VERSION 5.8 ;
BUSBITCHARS "[]" ;
DIVIDERCHAR "/" ;
UNITS
    DATABASE MICRONS 1000 ;
END UNITS

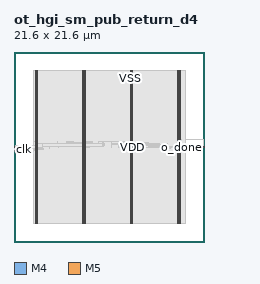
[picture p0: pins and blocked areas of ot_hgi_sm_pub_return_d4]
MACRO ot_hgi_sm_pub_return_d4
  FOREIGN ot_hgi_sm_pub_return_d4 0 0 ;
  CLASS BLOCK ;
  SIZE 21.6 BY 21.6 ;
  PIN clk
    DIRECTION INPUT ;
    USE SIGNAL ;
    PORT
      LAYER M4 ;
        RECT  0 10.512 0.084 10.536 ;
    END
  END clk
  PIN i_done
    DIRECTION INPUT ;
    USE SIGNAL ;
    PORT
      LAYER M4 ;
        RECT  0 10.608 0.084 10.632 ;
    END
  END i_done
  PIN i_fault
    DIRECTION INPUT ;
    USE SIGNAL ;
    PORT
      LAYER M4 ;
        RECT  0 10.704 0.084 10.728 ;
    END
  END i_fault
  PIN o_done
    DIRECTION OUTPUT ;
    USE SIGNAL ;
    PORT
      LAYER M4 ;
        RECT  21.516 10.704 21.6 10.728 ;
    END
  END o_done
  PIN o_fault
    DIRECTION OUTPUT ;
    USE SIGNAL ;
    PORT
      LAYER M4 ;
        RECT  21.516 10.8 21.6 10.824 ;
    END
  END o_fault
  PIN rn
    DIRECTION INPUT ;
    USE SIGNAL ;
    PORT
      LAYER M4 ;
        RECT  0 10.8 0.084 10.824 ;
    END
  END rn
  PIN VDD
    DIRECTION INOUT ;
    USE POWER ;
    PORT
      LAYER M5 ;
        RECT  18.792 2.151 18.912 19.449 ;
        RECT  13.392 2.151 13.512 19.449 ;
        RECT  7.992 2.151 8.112 19.449 ;
        RECT  2.592 2.151 2.712 19.449 ;
    END
  END VDD
  PIN VSS
    DIRECTION INOUT ;
    USE GROUND ;
    PORT
      LAYER M5 ;
        RECT  18.6 2.137 18.72 19.463 ;
        RECT  13.2 2.137 13.32 19.463 ;
        RECT  7.8 2.137 7.92 19.463 ;
        RECT  2.4 2.137 2.52 19.463 ;
    END
  END VSS
  # OT_OBS_CLOSED layer=M5 d_um=1.536 added=1
  OBS
    LAYER RVTN ;
     RECT  2.16 2.16 19.44 2.295 ;
     RECT  2.16 2.565 19.44 2.835 ;
     RECT  2.16 3.105 19.44 3.375 ;
     RECT  2.16 3.645 19.44 3.915 ;
     RECT  2.16 4.185 19.44 4.455 ;
     RECT  2.16 4.725 19.44 4.995 ;
     RECT  2.16 5.265 19.44 5.535 ;
     RECT  2.16 5.805 19.44 6.075 ;
     RECT  2.16 6.345 19.44 6.615 ;
     RECT  2.16 6.885 19.44 7.155 ;
     RECT  2.16 7.425 19.44 7.695 ;
     RECT  2.16 7.965 19.44 8.235 ;
     RECT  2.16 8.505 19.44 8.775 ;
     RECT  2.16 9.045 19.44 9.315 ;
     RECT  2.16 9.585 19.44 9.855 ;
     RECT  2.16 10.125 19.44 10.395 ;
     RECT  2.16 10.665 19.44 10.935 ;
     RECT  2.16 11.205 19.44 11.475 ;
     RECT  2.16 11.745 19.44 12.015 ;
     RECT  2.16 12.285 19.44 12.555 ;
     RECT  2.16 12.825 19.44 13.095 ;
     RECT  2.16 13.365 19.44 13.635 ;
     RECT  2.16 13.905 19.44 14.175 ;
     RECT  2.16 14.445 19.44 14.715 ;
     RECT  2.16 14.985 19.44 15.255 ;
     RECT  2.16 15.525 19.44 15.795 ;
     RECT  2.16 16.065 19.44 16.335 ;
     RECT  2.16 16.605 19.44 16.875 ;
     RECT  2.16 17.145 19.44 17.415 ;
     RECT  2.16 17.685 19.44 17.955 ;
     RECT  2.16 18.225 19.44 18.495 ;
     RECT  2.16 18.765 19.44 19.035 ;
     RECT  2.16 19.305 19.44 19.44 ;
    LAYER RVTP ;
     RECT  2.16 2.295 19.44 2.565 ;
     RECT  2.16 2.835 19.44 3.105 ;
     RECT  2.16 3.375 19.44 3.645 ;
     RECT  2.16 3.915 19.44 4.185 ;
     RECT  2.16 4.455 19.44 4.725 ;
     RECT  2.16 4.995 19.44 5.265 ;
     RECT  2.16 5.535 19.44 5.805 ;
     RECT  2.16 6.075 19.44 6.345 ;
     RECT  2.16 6.615 19.44 6.885 ;
     RECT  2.16 7.155 19.44 7.425 ;
     RECT  2.16 7.695 19.44 7.965 ;
     RECT  2.16 8.235 19.44 8.505 ;
     RECT  2.16 8.775 19.44 9.045 ;
     RECT  2.16 9.315 19.44 9.585 ;
     RECT  2.16 9.855 19.44 10.125 ;
     RECT  2.16 10.395 19.44 10.665 ;
     RECT  2.16 10.935 19.44 11.205 ;
     RECT  2.16 11.475 19.44 11.745 ;
     RECT  2.16 12.015 19.44 12.285 ;
     RECT  2.16 12.555 19.44 12.825 ;
     RECT  2.16 13.095 19.44 13.365 ;
     RECT  2.16 13.635 19.44 13.905 ;
     RECT  2.16 14.175 19.44 14.445 ;
     RECT  2.16 14.715 19.44 14.985 ;
     RECT  2.16 15.255 19.44 15.525 ;
     RECT  2.16 15.795 19.44 16.065 ;
     RECT  2.16 16.335 19.44 16.605 ;
     RECT  2.16 16.875 19.44 17.145 ;
     RECT  2.16 17.415 19.44 17.685 ;
     RECT  2.16 17.955 19.44 18.225 ;
     RECT  2.16 18.495 19.44 18.765 ;
     RECT  2.16 19.035 19.44 19.305 ;
    LAYER M1 ;
     RECT  2.16 2.151 19.44 19.449 ;
    LAYER M2 ;
     RECT  2.16 2.151 19.44 19.449 ;
     RECT  19.44 10.746 20.507 10.764 ;
     RECT  19.44 11.646 21.515 11.664 ;
    LAYER M3 ;
     RECT  2.415 2.143 2.505 2.413 ;
     RECT  7.815 2.143 7.905 2.413 ;
     RECT  13.215 2.143 13.305 2.413 ;
     RECT  18.615 2.143 18.705 2.413 ;
     RECT  2.415 2.413 2.697 10.435 ;
     RECT  18.615 2.413 18.897 10.435 ;
     RECT  2.304 10.435 2.697 10.471 ;
     RECT  13.215 2.413 13.497 10.471 ;
     RECT  18.54 10.435 18.897 10.471 ;
     RECT  2.304 10.471 3.366 10.589 ;
     RECT  18.54 10.471 19.134 10.625 ;
     RECT  12.924 10.471 13.497 10.633 ;
     RECT  16.884 10.597 16.902 10.633 ;
     RECT  17.748 10.597 17.766 10.633 ;
     RECT  7.815 2.413 8.097 10.705 ;
     RECT  2.304 10.589 3.222 10.733 ;
     RECT  12.06 10.669 12.078 10.741 ;
     RECT  12.852 10.633 13.497 10.741 ;
     RECT  16.884 10.633 17.766 10.741 ;
     RECT  18.54 10.625 19.098 10.741 ;
     RECT  2.304 10.733 2.697 10.795 ;
     RECT  14.832 10.741 14.85 10.795 ;
     RECT  20.484 10.741 20.502 10.829 ;
     RECT  16.488 10.741 19.098 10.859 ;
     RECT  7.815 10.705 8.55 10.867 ;
     RECT  10.08 10.831 10.098 10.891 ;
     RECT  11.844 10.741 13.698 10.895 ;
     RECT  16.488 10.859 17.766 10.895 ;
     RECT  14.832 10.795 15.318 10.939 ;
     RECT  16.488 10.895 17.442 10.939 ;
     RECT  7.815 10.867 9.162 10.975 ;
     RECT  5.04 10.741 5.058 11.011 ;
     RECT  7.74 10.975 9.162 11.011 ;
     RECT  10.08 10.891 10.17 11.011 ;
     RECT  3.996 10.597 4.086 11.039 ;
     RECT  6.84 11.011 9.162 11.101 ;
     RECT  11.052 10.741 11.07 11.101 ;
     RECT  11.844 10.895 13.497 11.101 ;
     RECT  14.832 10.939 17.442 11.129 ;
     RECT  18.54 10.859 19.098 11.129 ;
     RECT  5.04 11.011 5.202 11.137 ;
     RECT  6.768 11.101 9.162 11.165 ;
     RECT  10.08 11.011 10.314 11.165 ;
     RECT  15.012 11.129 16.506 11.165 ;
     RECT  6.768 11.165 8.874 11.173 ;
     RECT  4.248 11.137 5.202 11.201 ;
     RECT  11.052 11.101 13.497 11.201 ;
     RECT  4.248 11.201 4.986 11.213 ;
     RECT  11.916 11.201 13.497 11.237 ;
     RECT  15.3 11.165 15.894 11.237 ;
     RECT  17.424 11.129 17.442 11.237 ;
     RECT  10.08 11.165 10.098 11.245 ;
     RECT  11.916 11.237 11.934 11.261 ;
     RECT  15.3 11.237 15.318 11.261 ;
     RECT  6.048 11.173 8.874 11.281 ;
     RECT  5.976 11.281 8.874 11.309 ;
     RECT  5.976 11.309 6.786 11.399 ;
     RECT  7.815 11.309 8.874 11.399 ;
     RECT  9.612 11.245 10.098 11.399 ;
     RECT  11.052 11.201 11.07 11.399 ;
     RECT  2.268 10.795 2.697 11.435 ;
     RECT  4.968 11.213 4.986 11.435 ;
     RECT  5.976 11.399 5.994 11.435 ;
     RECT  6.768 11.399 6.786 11.435 ;
     RECT  9.684 11.399 10.098 11.435 ;
     RECT  18.576 11.129 19.098 11.435 ;
     RECT  10.08 11.435 10.098 11.453 ;
     RECT  12.708 11.237 13.497 11.453 ;
     RECT  21.492 10.699 21.51 11.669 ;
     RECT  18.615 11.435 19.098 11.705 ;
     RECT  2.415 11.435 2.697 19.187 ;
     RECT  7.815 11.399 8.097 19.187 ;
     RECT  13.215 11.453 13.497 19.187 ;
     RECT  18.615 11.705 18.897 19.187 ;
     RECT  2.415 19.187 2.505 19.457 ;
     RECT  7.815 19.187 7.905 19.457 ;
     RECT  13.215 19.187 13.305 19.457 ;
     RECT  18.615 19.187 18.705 19.457 ;
    LAYER M4 ;
     RECT  0.06 10.512 0.133 10.824 ;
     RECT  0.133 10.512 0.179 10.92 ;
     RECT  0.179 10.608 2.408 10.92 ;
     RECT  2.408 2.148 2.512 19.452 ;
     RECT  2.512 2.418 2.704 19.182 ;
     RECT  2.704 10.704 3.251 11.208 ;
     RECT  3.251 10.896 7.808 11.208 ;
     RECT  7.808 2.148 7.912 19.452 ;
     RECT  7.912 2.418 8.104 19.182 ;
     RECT  8.104 10.896 10.069 11.16 ;
     RECT  10.069 10.896 10.181 11.448 ;
     RECT  10.181 11.424 11.905 11.448 ;
     RECT  11.905 11.232 12.044 11.448 ;
     RECT  12.044 10.704 12.131 11.448 ;
     RECT  12.131 11.232 13.208 11.448 ;
     RECT  13.208 2.148 13.312 19.452 ;
     RECT  13.312 2.418 13.504 19.182 ;
     RECT  13.504 11.232 15.289 11.256 ;
     RECT  15.289 10.8 15.329 11.256 ;
     RECT  15.329 10.8 16.913 10.824 ;
     RECT  18.608 2.148 18.712 19.452 ;
     RECT  18.712 2.418 18.904 19.182 ;
     RECT  20.473 10.8 21.481 10.824 ;
     RECT  21.481 10.704 21.564 10.824 ;
    LAYER M5 ;
     RECT  2.4 2.137 2.52 2.151 ;
     RECT  7.8 2.137 7.92 2.151 ;
     RECT  13.2 2.137 13.32 2.151 ;
     RECT  18.6 2.137 18.72 2.151 ;
     RECT  2.4 2.151 2.712 10.693 ;
     RECT  0.144 10.501 0.168 10.931 ;
     RECT  2.4 10.693 3.24 11.219 ;
     RECT  12.096 10.693 12.12 11.267 ;
     RECT  2.4 11.219 2.712 19.449 ;
     RECT  7.8 2.151 8.112 19.449 ;
     RECT  13.2 2.151 13.512 19.449 ;
     RECT  18.6 2.151 18.912 19.449 ;
     RECT  2.4 19.449 2.52 19.463 ;
     RECT  7.8 19.449 7.92 19.463 ;
     RECT  13.2 19.449 13.32 19.463 ;
     RECT  18.6 19.449 18.72 19.463 ;
     RECT  12.12 10.693 13.2 11.267 ;
  END
END ot_hgi_sm_pub_return_d4
END LIBRARY
